VERSION 5.7 ;

BUSBITCHARS "[]" ;
DIVIDERCHAR "/" ;

UNITS
  DATABASE MICRONS 1000 ;
END UNITS

MANUFACTURINGGRID 0.005 ;

PROPERTYDEFINITIONS
  LAYER LEF58_TYPE STRING ;
END PROPERTYDEFINITIONS

SITE CoreSite
  CLASS CORE ;
  SYMMETRY Y ;
  SIZE 30 BY 30 ;
END CoreSite

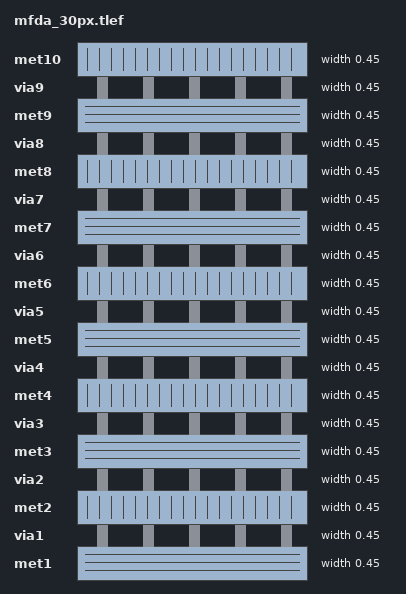
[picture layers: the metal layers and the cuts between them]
LAYER met1
  TYPE ROUTING ;
  DIRECTION HORIZONTAL ;
  MINWIDTH 0.45 ;
  WIDTH 0.45 ;
END met1

LAYER via1
  TYPE CUT ;
  WIDTH 0.45 ;
END via1

LAYER met2
  TYPE ROUTING ;
  DIRECTION VERTICAL ;
  MINWIDTH 0.45 ;
  WIDTH 0.45 ;
END met2

LAYER via2
  TYPE CUT ;
  WIDTH 0.45 ;
END via2

LAYER met3
  TYPE ROUTING ;
  DIRECTION HORIZONTAL ;
  MINWIDTH 0.45 ;
  WIDTH 0.45 ;
END met3

LAYER via3
  TYPE CUT ;
  WIDTH 0.45 ;
END via3

LAYER met4
  TYPE ROUTING ;
  DIRECTION VERTICAL ;
  MINWIDTH 0.45 ;
  WIDTH 0.45 ;
END met4

LAYER via4
  TYPE CUT ;
  WIDTH 0.45 ;
END via4

LAYER met5
  TYPE ROUTING ;
  DIRECTION HORIZONTAL ;
  MINWIDTH 0.45 ;
  WIDTH 0.45 ;
END met5

LAYER via5
  TYPE CUT ;
  WIDTH 0.45 ;
END via5

LAYER met6
  TYPE ROUTING ;
  DIRECTION VERTICAL ;
  MINWIDTH 0.45 ;
  WIDTH 0.45 ;
END met6

LAYER via6
  TYPE CUT ;
  WIDTH 0.45 ;
END via6

LAYER met7
  TYPE ROUTING ;
  DIRECTION HORIZONTAL ;
  MINWIDTH 0.45 ;
  WIDTH 0.45 ;
END met7

LAYER via7
  TYPE CUT ;
  WIDTH 0.45 ;
END via7

LAYER met8
  TYPE ROUTING ;
  DIRECTION VERTICAL ;
  MINWIDTH 0.45 ;
  WIDTH 0.45 ;
END met8

LAYER via8
  TYPE CUT ;
  WIDTH 0.45 ;
END via8

LAYER met9
  TYPE ROUTING ;
  DIRECTION HORIZONTAL ;
  MINWIDTH 0.45 ;
  WIDTH 0.45 ;
END met9

LAYER via9
  TYPE CUT ;
  WIDTH 0.45 ;
END via9

LAYER met10
  TYPE ROUTING ;
  DIRECTION VERTICAL ;
  MINWIDTH 0.45 ;
  WIDTH 0.45 ;
END met10

VIA M1M2_PR DEFAULT
  LAYER via1 ;
    RECT -0.225 -0.225 0.225 0.225 ;
  LAYER met1 ;
    RECT -0.225 -0.225 0.225 0.225 ;
  LAYER met2 ;
    RECT -0.225 -0.225 0.225 0.225 ;
END M1M2_PR

VIA M2M3_PR DEFAULT
  LAYER via2 ;
    RECT -0.225 -0.225 0.225 0.225 ;
  LAYER met2 ;
    RECT -0.225 -0.225 0.225 0.225 ;
  LAYER met3 ;
    RECT -0.225 -0.225 0.225 0.225 ;
END M2M3_PR

VIA M3M4_PR DEFAULT
  LAYER via3 ;
    RECT -0.225 -0.225 0.225 0.225 ;
  LAYER met3 ;
    RECT -0.225 -0.225 0.225 0.225 ;
  LAYER met4 ;
    RECT -0.225 -0.225 0.225 0.225 ;
END M3M4_PR

VIA M4M5_PR DEFAULT
  LAYER via4 ;
    RECT -0.225 -0.225 0.225 0.225 ;
  LAYER met4 ;
    RECT -0.225 -0.225 0.225 0.225 ;
  LAYER met5 ;
    RECT -0.225 -0.225 0.225 0.225 ;
END M4M5_PR

VIA M5M6_PR DEFAULT
  LAYER via5 ;
    RECT -0.225 -0.225 0.225 0.225 ;
  LAYER met5 ;
    RECT -0.225 -0.225 0.225 0.225 ;
  LAYER met6 ;
    RECT -0.225 -0.225 0.225 0.225 ;
END M5M6_PR

VIA M6M7_PR DEFAULT
  LAYER via6 ;
    RECT -0.225 -0.225 0.225 0.225 ;
  LAYER met6 ;
    RECT -0.225 -0.225 0.225 0.225 ;
  LAYER met7 ;
    RECT -0.225 -0.225 0.225 0.225 ;
END M6M7_PR

VIA M7M8_PR DEFAULT
  LAYER via7 ;
    RECT -0.225 -0.225 0.225 0.225 ;
  LAYER met7 ;
    RECT -0.225 -0.225 0.225 0.225 ;
  LAYER met8 ;
    RECT -0.225 -0.225 0.225 0.225 ;
END M7M8_PR

VIA M8M9_PR DEFAULT
  LAYER via8 ;
    RECT -0.225 -0.225 0.225 0.225 ;
  LAYER met8 ;
    RECT -0.225 -0.225 0.225 0.225 ;
  LAYER met9 ;
    RECT -0.225 -0.225 0.225 0.225 ;
END M8M9_PR

VIA M9M10_PR DEFAULT
  LAYER via9 ;
    RECT -0.225 -0.225 0.225 0.225 ;
  LAYER met9 ;
    RECT -0.225 -0.225 0.225 0.225 ;
  LAYER met10 ;
    RECT -0.225 -0.225 0.225 0.225 ;
END M9M10_PR

END LIBRARY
